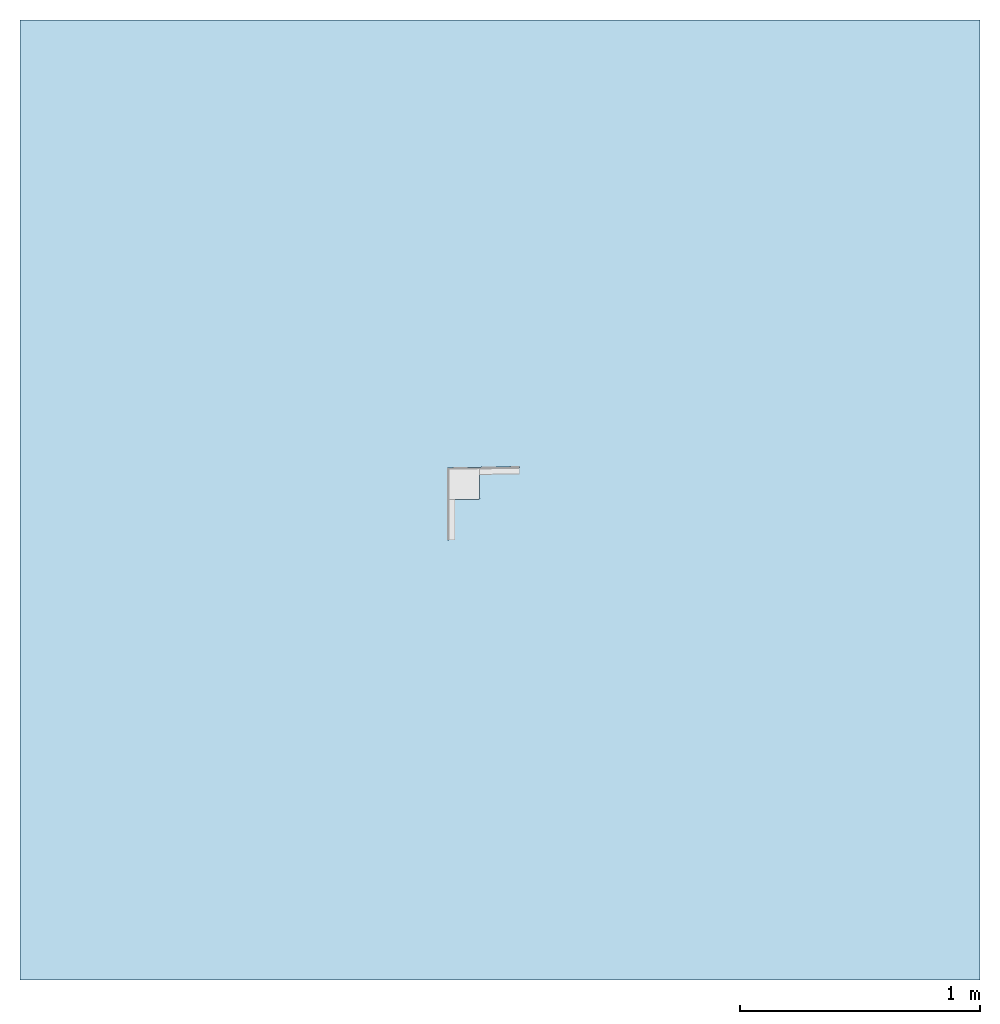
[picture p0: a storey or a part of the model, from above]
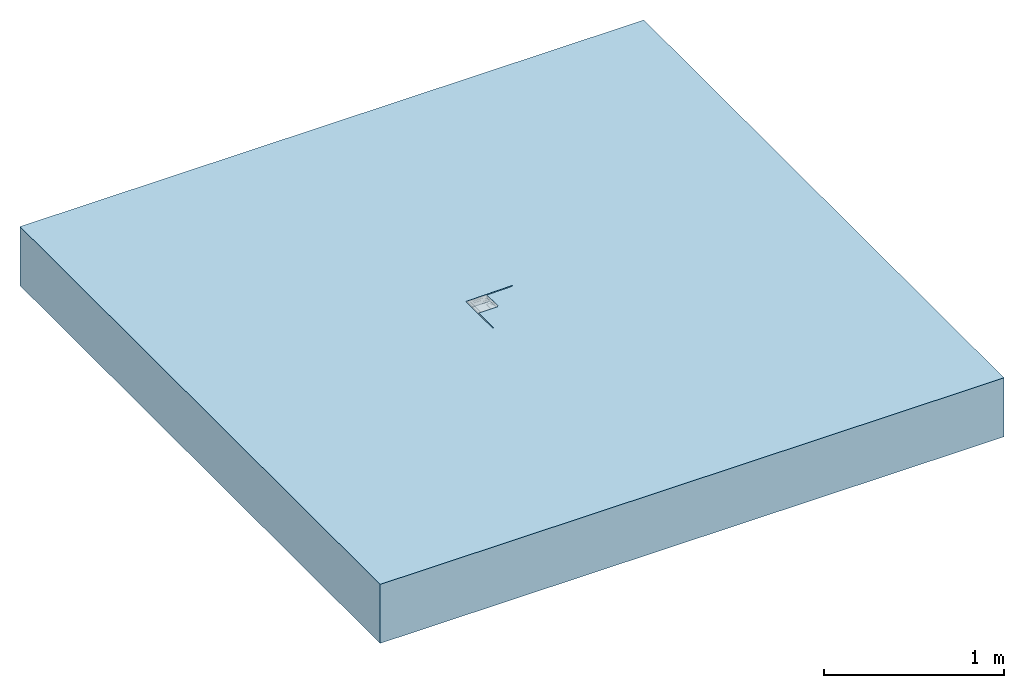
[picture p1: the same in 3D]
Properties of the parts of a building model (IFC2X3)

# File
Description: ViewDefinition [CoordinationView]
File name: Project Number
Time: 2014-06-06T11:38:58
Written by: The EXPRESS Data Manager Version 5.01.0100.02.64mod : 6 Jun 2012
Made in: 20130308_1515(x64) - Exporter 2014.0.2013.0308 - Default UI
Comment: STEP Physical File produced by: The EXPRESS Data Manager Version 5.01.0100.02.64mod : 6 Jun 2012 * Module: EDMstepFileFactory/EDMstandAlone * Creation date: Fri Jun 06 11:38:58 2014 * Host: IN-BLR-PC-0010 * Database: C:\Users\palleri\AppData\Local\Temp\{6184EEF1-637C-41C5-823D-7F270C337190}\ifc * Database version: 5507 * Database creation date: Fri Jun 06 11:38:57 2014 * Schema: IFC2X3 * Model: DataRepository.ifc * Model creation date: Fri Jun 06 11:38:57 2014 * Header model: DataRepository.ifc_HeaderModel * Header model creation date: Fri Jun 06 11:38:57 2014 * EDMuser: sdai-user * EDMgroup: sdai-group * License ID and type: 5605 : Permanent license. Expiry date: * EDMstepFileFactory options: 020000

# IfcProject, Project Number
LongName: Project Name; Phase: Project Status

# IfcSite, Default
RefLatitude: 42, 21, 30, 344238; RefLongitude: -71, -3, -35, -194702; RefElevation: 0 mm

# IfcBuilding
Pset_BuildingCommon - NumberOfStoreys: 1
Other - Project Address: ## Street City, State Zip; Project Name: Project Name; Project Number: Project Number; Project Status: Project Status; Client Name: Owner; Project Issue Date: Issue Date

# IfcBuildingStorey, Level 1
LongName: Level 1; Elevation: 0 mm
Constraints - Elevation Base: Project Base Point; Elevation: 0 mm
Graphics - Line Pattern: Center; Symbol at End 1 Default: no; Color: 0; Line Weight: 1; Symbol: M_Level Head - Circle: M_Level Head - Circle; Symbol at End 2 Default: yes
Identity Data - Building Story: yes; Structural: no; Name: Level 1
Dimensions - Computation Height: 0 mm

# IfcFlowTerminal: 38634F - Adjustable Corner - Fixed Height Channel, ACO Freedeck Adjustable Length (Accessories part 2) V1.12 - Galvanized Steel:38634F - Adjustable Corner - Fixed Height Channel:287534
In: Level 1
Material: Galvanized Steel
Dimensions - Corner Angle Void Position: 0 mm; Grating End Length: 600 mm; Channel End Length: -600 mm; Channel Length: 600 mm; Height @ Invert 2: 165 mm; Height @ Invert 1: 165 mm; Corner Angle Gravel Guard: 73 mm; Adjustable Corner Angle: 91 deg
Identity Data - Mark: 19; Watermarked By: www.acobd.com; E-mail Sales: abdcommercial@aco.co.uk; Address: ACO Business Centre, Caxton Road, Bedford, MK41 0LF; Watermark1: This file is the property of ACO Technologies PLC; Fax: +44 (0)1462 851490; Watermark2: This file is water marked and users are prohibited to reproduce, adapt, distribute this information; Watermarked With: BIM Manager Premium Suite; Website: www.acobd.com; Telephone: +44 (0)1462 816666; E-mail Technical: abdtechnical@aco.co.uk; Manufacturer: ACO Building Drainage
Other - Height @ Invert 2 Min & Max: 5000 mm; Height @ Invert 1 Min & Max: 5000 mm; Nos: 20; Corner Angle Value: 91 deg; Corner Angle Invert Height Min & Max: 75 mm; Top Piece Void Height @ Invert 1: 31 mm; Top Piece Void Height @ Invert 2: 31 mm; Corner Angle Fixed Height: yes; Corner Angle Adjustable Height: yes; Base Height: 46 mm; Top Height: 50 mm; Adjustable Length Deep Section: no; Top Void Position: 5000 mm; Adjustable Length Intermediate Section: no; Adjustable Length Shallow Section: no; Adjustable Length Channel: no
Construction - Corner Angle Shallow Section: no; 00277 - Grating - Slotted Grating - Galvanised Steel - 500mm long: no; 36952 - Grating - Plain Mesh - Galvanised Steel - 500mm long: yes; Corner Angle Intermediate Section: no
Constraints - Level: Level: Level 1; Moves With Nearby Elements: no
Phasing - Phase Created: New Construction
Pset_ManufacturerTypeInformation - Manufacturer: ACO Building Drainage
General - Price: POA - contact ACO; Channel Recycled Material Content: 25 - 30 %; Installation Guidelines: X:\Electronic Literature\ABD Electronic Literature\Roof and Balcony Drainage\ACO Freedeck Brochure.pdf; Channel Colour: Galvanised; Load Class: A15; Product Standard: BS EN 1433:2002, CE marked; Product Code: 38634F; Weight (Kg): 1.5kg; Dimensions (LxWxH): 300 x 300; Product Range: ACO Freedeck; NBS Specification: NBS Section R10 Gravity Rainwater Drainage Systems, Subsection 365; Product Description: ACO Freedeck Adjustable Corner - Fixed Height channel section only; Channel Recyclable: Fully recyclable; Channel Material: Hot Dipped Galvanised Steel; Maintenance Guidelines: X:\Electronic Literature\ABD Electronic Literature\Roof and Balcony Drainage\ACO Freedeck Brochure.pdf; Product Type: Linear Deck Drainage System
Materials and Finishes - Material: Galvanized Steel
Model Properties - Grating Product Code 00277: N/A; Grating Product Code 36952: N/A

# IfcOpeningElement: Recess (2)
In: Level 1
Dimensions - Perimeter: 16000 mm; Volume: 6.39762 m3; Area: 16 m2; Thickness: 400 mm
Structural - Structural: no; Enable Analytical Model: no
Phasing - Phase Created: New Construction
Constraints - Level: Level: Level 1; Related to Mass: no; Room Bounding: yes; Height Offset From Level: 0 mm
Analytical Properties - Absorptance: 0.1; Thermal mass: 604440; Roughness: 1; Thermal Resistance (R): 0.382409; Heat Transfer Coefficient (U): 2.615
Construction - Default Thickness: 400 mm; Function: Interior
Materials and Finishes - Structural Material: Concrete, Broom Finish
Graphics - Coarse Scale Fill Color: 0

# IfcSlab: Floor:Generic Floor - 400mm, Floor:Generic Floor - 400mm:193825
In: Level 1
PredefinedType: FLOOR; Material: Concrete, Broom Finish 400 mm
Dimensions - Perimeter: 16000 mm; Volume: 6.39762 m3; Area: 16 m2; Thickness: 400 mm
Structural - Structural: no; Enable Analytical Model: no
Phasing - Phase Created: New Construction
Constraints - Level: Level: Level 1; Related to Mass: no; Room Bounding: yes; Height Offset From Level: 0 mm
Pset_SlabCommon - Reference: Generic Floor - 400mm; IsExternal: no; LoadBearing: yes; ThermalTransmittance: 2.615 kg/K/s3
Analytical Properties - Absorptance: 0.1; Thermal mass: 604440; Roughness: 1; Thermal Resistance (R): 0.382409; Heat Transfer Coefficient (U): 2.615
Construction - Default Thickness: 400 mm; Function: Interior
Materials and Finishes - Structural Material: Concrete, Broom Finish
Graphics - Coarse Scale Fill Color: 0
